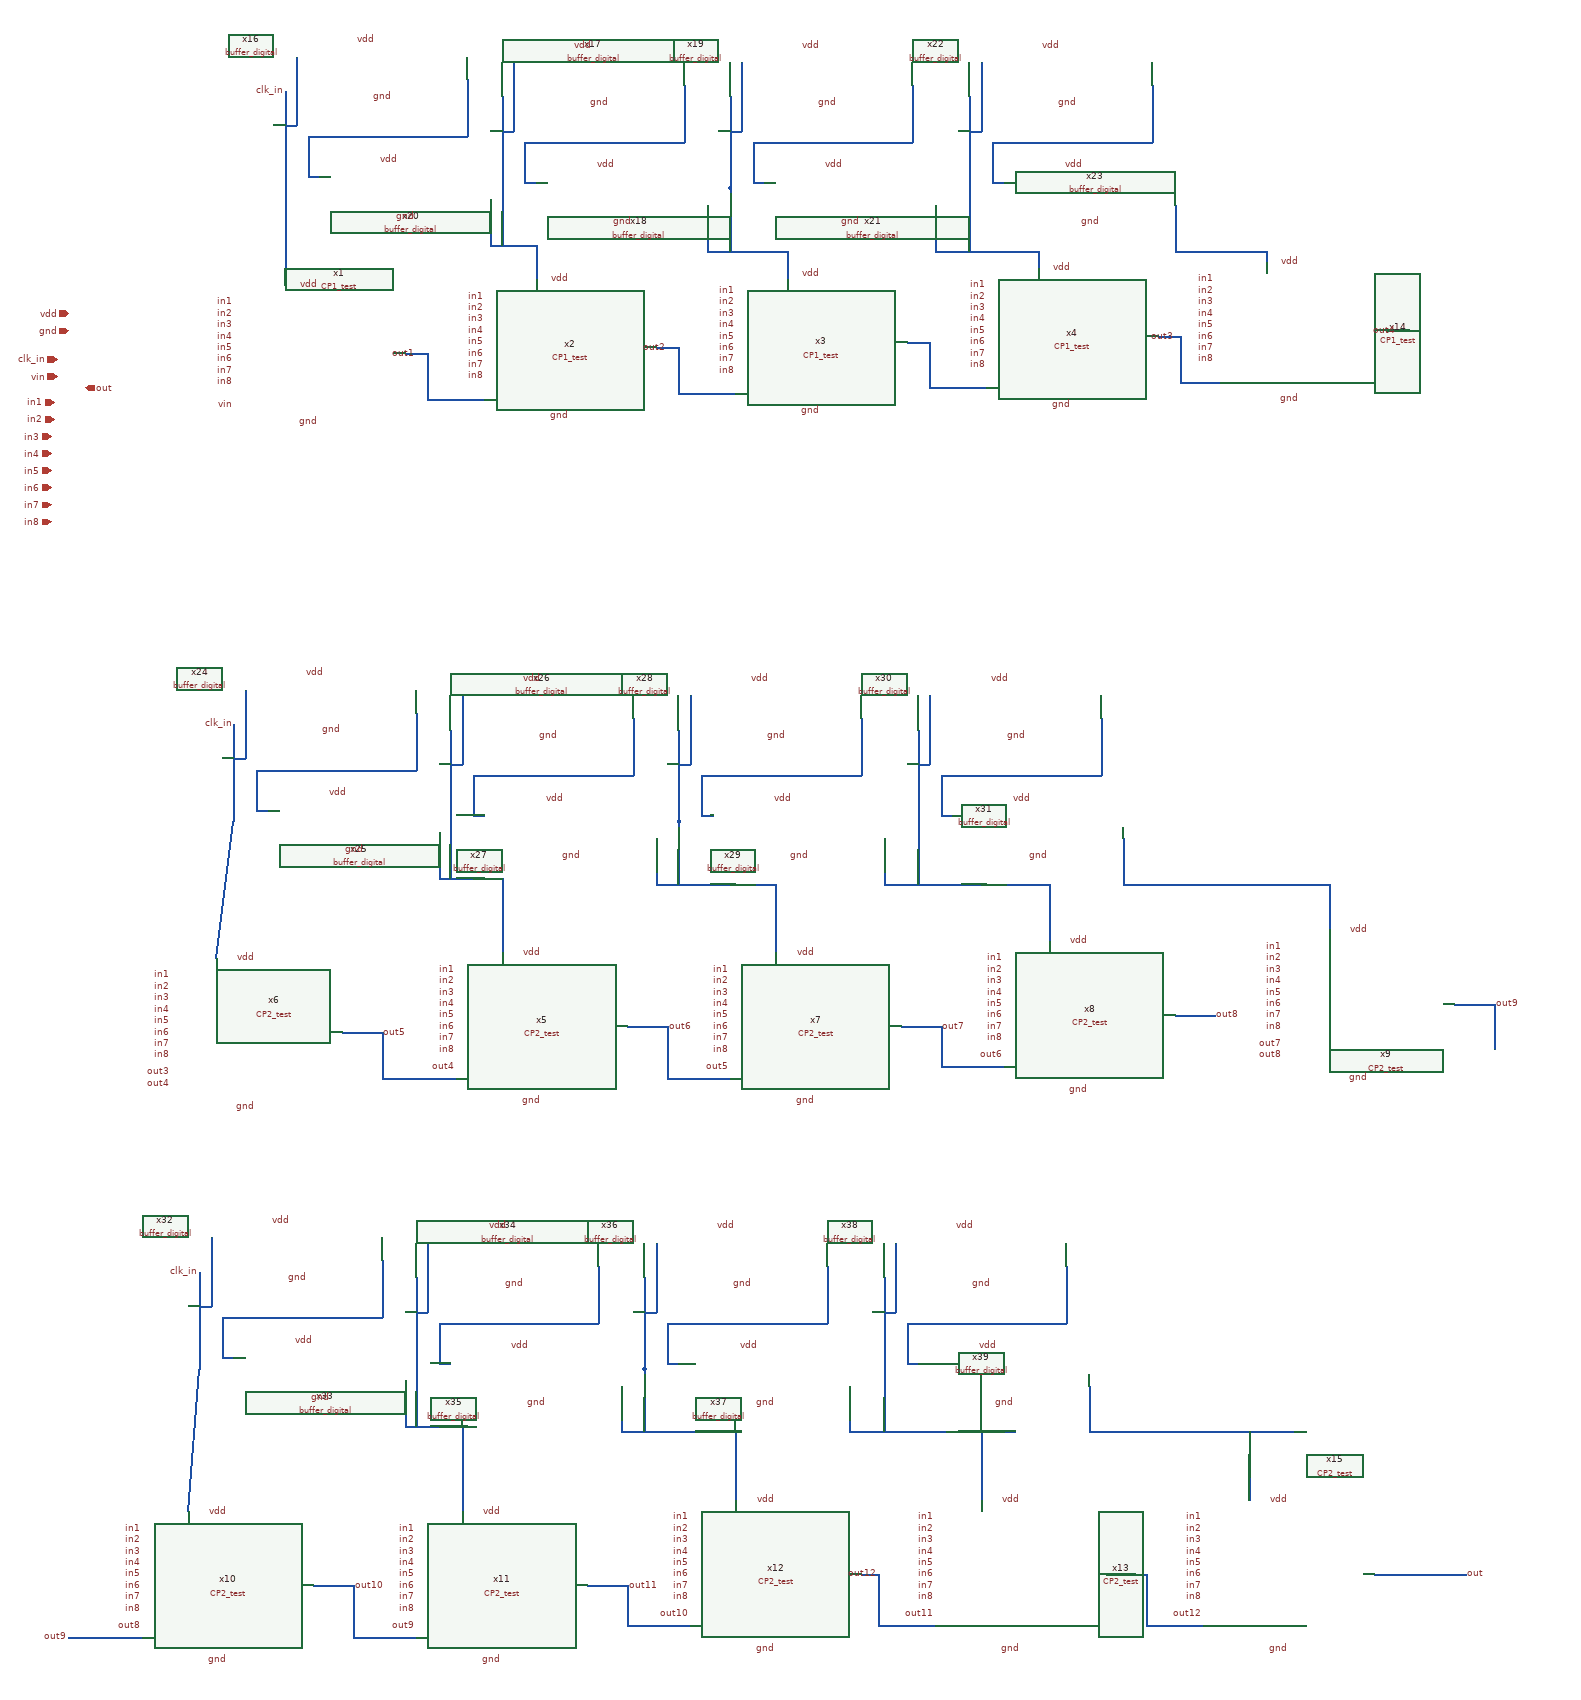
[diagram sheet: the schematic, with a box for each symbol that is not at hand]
v {xschem version=3.4.4 file_version=1.2
}
G {}
K {}
V {}
S {}
E {}
N -340 1800 -300 1800 {
lab=out1}
N 100 1790 140 1790 {
lab=out2}
N -300 1880 -200 1880 {
lab=out1}
N -300 1800 -300 1880 {
lab=out1}
N 540 1780 580 1780 {
lab=#net1}
N 140 1790 140 1870 {
lab=out2}
N 140 1870 240 1870 {
lab=out2}
N 980 1770 1020 1770 {
lab=out3}
N 580 1860 680 1860 {
lab=#net1}
N 580 1780 580 1860 {
lab=#net1}
N -450 2990 -380 2990 {
lab=out5}
N 50 2980 120 2980 {
lab=out6}
N 530 2980 600 2980 {
lab=out7}
N 1010 2960 1080 2960 {
lab=out8}
N -380 2990 -380 3070 {
lab=out5}
N -380 3070 -250 3070 {
lab=out5}
N 120 2980 120 3070 {
lab=out6}
N 120 3070 230 3070 {
lab=out6}
N 600 2980 600 3050 {
lab=out7}
N 600 3050 710 3050 {
lab=out7}
N 1500 2940 1570 2940 {
lab=out9}
N -500 3960 -430 3960 {
lab=out10}
N -20 3960 50 3960 {
lab=out11}
N 1570 2940 1570 3020 {
lab=out9}
N -930 4050 -800 4050 {
lab=out9}
N -430 3960 -430 4050 {
lab=out10}
N -430 4050 -320 4050 {
lab=out10}
N 50 3960 50 4030 {
lab=out11}
N 50 4030 160 4030 {
lab=out11}
N 460 3940 490 3940 {
lab=out12}
N 490 3940 490 4030 {
lab=out12}
N 490 4030 590 4030 {
lab=out12}
N 1380 1760 1420 1760 {
lab=out4}
N 1020 1770 1020 1850 {
lab=out3}
N 1020 1850 1090 1850 {
lab=out3}
N 1360 3940 1430 3940 {
lab=out}
N 930 3940 960 3940 {
lab=#net2}
N 960 3940 960 4030 {
lab=#net2}
N 960 4030 1060 4030 {
lab=#net2}
N 890 3940 940 3940 {
lab=#net2}
N 1430 3940 1520 3940 {
lab=out}
N -550 1500 -550 1510 {
lab=clk_in}
N -550 1510 -550 1670 {
lab=clk_in}
N -550 1660 -550 1680 {
lab=clk_in}
N -550 1340 -550 1500 {
lab=clk_in}
N -550 1400 -530 1400 {
lab=clk_in}
N -230 1360 -230 1420 {
lab=#net3}
N -510 1420 -230 1420 {
lab=#net3}
N -510 1420 -510 1490 {
lab=#net3}
N -510 1490 -490 1490 {
lab=#net3}
N -190 1610 -110 1610 {
lab=#net4}
N -110 1610 -110 1670 {
lab=#net4}
N -230 1320 -230 1350 {
lab=#net3}
N -230 1350 -230 1360 {
lab=#net3}
N -530 1280 -530 1400 {
lab=clk_in}
N -190 1530 -190 1610 {
lab=#net4}
N -170 1510 -170 1520 {
lab=#net4}
N -170 1350 -170 1510 {
lab=#net4}
N -170 1410 -150 1410 {
lab=#net4}
N 150 1370 150 1430 {
lab=#net5}
N -130 1430 150 1430 {
lab=#net5}
N -130 1430 -130 1500 {
lab=#net5}
N -130 1500 -110 1500 {
lab=#net5}
N 150 1330 150 1360 {
lab=#net5}
N 150 1360 150 1370 {
lab=#net5}
N -150 1290 -150 1410 {
lab=#net4}
N 190 1540 190 1620 {
lab=#net6}
N 230 1510 230 1520 {
lab=#net6}
N 230 1350 230 1510 {
lab=#net6}
N 230 1410 250 1410 {
lab=#net6}
N 550 1370 550 1430 {
lab=#net7}
N 270 1430 550 1430 {
lab=#net7}
N 270 1430 270 1500 {
lab=#net7}
N 270 1500 290 1500 {
lab=#net7}
N 550 1330 550 1360 {
lab=#net7}
N 550 1360 550 1370 {
lab=#net7}
N 250 1290 250 1410 {
lab=#net6}
N 590 1540 590 1620 {
lab=#net8}
N 650 1510 650 1520 {
lab=#net8}
N 650 1350 650 1510 {
lab=#net8}
N 650 1410 670 1410 {
lab=#net8}
N 970 1370 970 1430 {
lab=#net9}
N 690 1430 970 1430 {
lab=#net9}
N 690 1430 690 1500 {
lab=#net9}
N 690 1500 710 1500 {
lab=#net9}
N 970 1330 970 1360 {
lab=#net9}
N 970 1360 970 1370 {
lab=#net9}
N 670 1290 670 1410 {
lab=#net8}
N 1010 1540 1010 1620 {
lab=#net10}
N -170 1520 -170 1610 {
lab=#net4}
N 190 1620 330 1620 {
lab=#net6}
N 330 1620 330 1670 {
lab=#net6}
N 230 1510 230 1620 {
lab=#net6}
N 590 1620 770 1620 {
lab=#net8}
N 770 1620 770 1650 {
lab=#net8}
N 650 1520 650 1620 {
lab=#net8}
N 1010 1620 1170 1620 {
lab=#net10}
N 1170 1620 1170 1640 {
lab=#net10}
N -640 2610 -640 2620 {
lab=clk_in}
N -640 2450 -640 2610 {
lab=clk_in}
N -640 2510 -620 2510 {
lab=clk_in}
N -320 2470 -320 2530 {
lab=#net11}
N -600 2530 -320 2530 {
lab=#net11}
N -600 2530 -600 2600 {
lab=#net11}
N -600 2600 -580 2600 {
lab=#net11}
N -280 2720 -200 2720 {
lab=#net12}
N -320 2430 -320 2460 {
lab=#net11}
N -320 2460 -320 2470 {
lab=#net11}
N -620 2390 -620 2510 {
lab=clk_in}
N -280 2640 -280 2720 {
lab=#net12}
N -260 2620 -260 2630 {
lab=#net12}
N -260 2460 -260 2620 {
lab=#net12}
N -260 2520 -240 2520 {
lab=#net12}
N 60 2480 60 2540 {
lab=#net13}
N -220 2540 60 2540 {
lab=#net13}
N -220 2540 -220 2610 {
lab=#net13}
N -220 2610 -200 2610 {
lab=#net13}
N 60 2440 60 2470 {
lab=#net13}
N 60 2470 60 2480 {
lab=#net13}
N -240 2400 -240 2520 {
lab=#net12}
N 100 2650 100 2730 {
lab=#net14}
N 140 2620 140 2630 {
lab=#net14}
N 140 2460 140 2620 {
lab=#net14}
N 140 2520 160 2520 {
lab=#net14}
N 460 2480 460 2540 {
lab=#net15}
N 180 2540 460 2540 {
lab=#net15}
N 180 2540 180 2610 {
lab=#net15}
N 180 2610 200 2610 {
lab=#net15}
N 460 2440 460 2470 {
lab=#net15}
N 460 2470 460 2480 {
lab=#net15}
N 160 2400 160 2520 {
lab=#net14}
N 500 2650 500 2730 {
lab=#net16}
N 560 2620 560 2630 {
lab=#net16}
N 560 2460 560 2620 {
lab=#net16}
N 560 2520 580 2520 {
lab=#net16}
N 880 2480 880 2540 {
lab=#net17}
N 600 2540 880 2540 {
lab=#net17}
N 600 2540 600 2610 {
lab=#net17}
N 600 2610 620 2610 {
lab=#net17}
N 880 2440 880 2470 {
lab=#net17}
N 880 2470 880 2480 {
lab=#net17}
N 580 2400 580 2520 {
lab=#net16}
N 920 2650 920 2730 {
lab=#net18}
N -260 2630 -260 2720 {
lab=#net12}
N 100 2730 240 2730 {
lab=#net14}
N 140 2620 140 2730 {
lab=#net14}
N 500 2730 680 2730 {
lab=#net16}
N 560 2630 560 2730 {
lab=#net16}
N 920 2730 1080 2730 {
lab=#net18}
N -670 2860 -640 2620 {
lab=clk_in}
N -170 2720 -170 2850 {
lab=#net12}
N -220 2720 -170 2720 {
lab=#net12}
N 310 2730 310 2850 {
lab=#net14}
N 230 2730 310 2730 {
lab=#net14}
N 790 2730 790 2830 {
lab=#net16}
N 670 2730 790 2730 {
lab=#net16}
N 1080 2730 1280 2730 {
lab=#net18}
N 1280 2730 1280 2810 {
lab=#net18}
N -700 3570 -700 3580 {
lab=clk_in}
N -700 3410 -700 3570 {
lab=clk_in}
N -700 3470 -680 3470 {
lab=clk_in}
N -380 3430 -380 3490 {
lab=#net19}
N -660 3490 -380 3490 {
lab=#net19}
N -660 3490 -660 3560 {
lab=#net19}
N -660 3560 -640 3560 {
lab=#net19}
N -340 3680 -260 3680 {
lab=#net20}
N -380 3390 -380 3420 {
lab=#net19}
N -380 3420 -380 3430 {
lab=#net19}
N -680 3350 -680 3470 {
lab=clk_in}
N -340 3600 -340 3680 {
lab=#net20}
N -320 3580 -320 3590 {
lab=#net20}
N -320 3420 -320 3580 {
lab=#net20}
N -320 3480 -300 3480 {
lab=#net20}
N 0 3440 0 3500 {
lab=#net21}
N -280 3500 0 3500 {
lab=#net21}
N -280 3500 -280 3570 {
lab=#net21}
N -280 3570 -260 3570 {
lab=#net21}
N 0 3400 0 3430 {
lab=#net21}
N 0 3430 0 3440 {
lab=#net21}
N -300 3360 -300 3480 {
lab=#net20}
N 40 3610 40 3690 {
lab=#net22}
N 80 3580 80 3590 {
lab=#net22}
N 80 3420 80 3580 {
lab=#net22}
N 80 3480 100 3480 {
lab=#net22}
N 400 3440 400 3500 {
lab=#net23}
N 120 3500 400 3500 {
lab=#net23}
N 120 3500 120 3570 {
lab=#net23}
N 120 3570 140 3570 {
lab=#net23}
N 400 3400 400 3430 {
lab=#net23}
N 400 3430 400 3440 {
lab=#net23}
N 100 3360 100 3480 {
lab=#net22}
N 440 3610 440 3690 {
lab=#net24}
N 500 3580 500 3590 {
lab=#net24}
N 500 3420 500 3580 {
lab=#net24}
N 500 3480 520 3480 {
lab=#net24}
N 820 3440 820 3500 {
lab=#net25}
N 540 3500 820 3500 {
lab=#net25}
N 540 3500 540 3570 {
lab=#net25}
N 540 3570 560 3570 {
lab=#net25}
N 820 3400 820 3430 {
lab=#net25}
N 820 3430 820 3440 {
lab=#net25}
N 520 3360 520 3480 {
lab=#net24}
N 860 3610 860 3690 {
lab=#net26}
N -320 3590 -320 3680 {
lab=#net20}
N 40 3690 180 3690 {
lab=#net22}
N 80 3580 80 3690 {
lab=#net22}
N 440 3690 620 3690 {
lab=#net24}
N 500 3590 500 3690 {
lab=#net24}
N 860 3690 1020 3690 {
lab=#net26}
N -280 3680 -230 3680 {
lab=#net20}
N 170 3690 250 3690 {
lab=#net22}
N 610 3690 730 3690 {
lab=#net24}
N 1020 3690 1220 3690 {
lab=#net26}
N -720 3830 -700 3580 {
lab=clk_in}
N -240 3680 -240 3830 {
lab=#net20}
N 240 3690 240 3810 {
lab=#net22}
N 670 3690 670 3810 {
lab=#net24}
N 1140 3690 1140 3810 {
lab=#net26}
C {CP1_test.sym} -490 1800 0 0 {name=x1}
C {devices/lab_pin.sym} -490 1680 1 0 {name=p12 sig_type=std_logic lab=vdd}
C {devices/lab_pin.sym} -550 1340 1 0 {name=p13 sig_type=std_logic lab=clk_in}
C {devices/lab_pin.sym} -640 1710 0 0 {name=p14 sig_type=std_logic lab=in1
value=0}
C {devices/lab_pin.sym} -640 1730 0 0 {name=p15 sig_type=std_logic lab=in2
value=0}
C {devices/lab_pin.sym} -640 1750 0 0 {name=p16 sig_type=std_logic lab=in3
value=0}
C {devices/lab_pin.sym} -640 1770 0 0 {name=p17 sig_type=std_logic lab=in4
value=0}
C {devices/lab_pin.sym} -640 1790 0 0 {name=p18 sig_type=std_logic lab=in5
value=0}
C {devices/lab_pin.sym} -640 1810 0 0 {name=p19 sig_type=std_logic lab=in6
value=0}
C {devices/lab_pin.sym} -640 1830 0 0 {name=p20 sig_type=std_logic lab=in7
value=0}
C {devices/lab_pin.sym} -640 1850 0 0 {name=p21 sig_type=std_logic lab=in8
value=0}
C {devices/lab_pin.sym} -640 1890 0 0 {name=p22 sig_type=std_logic lab=vin}
C {CP1_test.sym} -50 1790 0 0 {name=x2}
C {devices/lab_pin.sym} -50 1670 1 0 {name=p23 sig_type=std_logic lab=vdd}
C {devices/lab_pin.sym} -200 1700 0 0 {name=p25 sig_type=std_logic lab=in1
value=0}
C {devices/lab_pin.sym} -200 1720 0 0 {name=p26 sig_type=std_logic lab=in2
value=0}
C {devices/lab_pin.sym} -200 1740 0 0 {name=p27 sig_type=std_logic lab=in3
value=0}
C {devices/lab_pin.sym} -200 1760 0 0 {name=p28 sig_type=std_logic lab=in4
value=0}
C {devices/lab_pin.sym} -200 1780 0 0 {name=p29 sig_type=std_logic lab=in5
value=0}
C {devices/lab_pin.sym} -200 1800 0 0 {name=p30 sig_type=std_logic lab=in6
value=0}
C {devices/lab_pin.sym} -200 1820 0 0 {name=p31 sig_type=std_logic lab=in7
value=0}
C {devices/lab_pin.sym} -200 1840 0 0 {name=p32 sig_type=std_logic lab=in8
value=0}
C {devices/lab_pin.sym} -320 1800 1 0 {name=p33 sig_type=std_logic lab=out1}
C {CP1_test.sym} 390 1780 0 0 {name=x3}
C {devices/lab_pin.sym} 390 1660 1 0 {name=p34 sig_type=std_logic lab=vdd}
C {devices/lab_pin.sym} 240 1690 0 0 {name=p36 sig_type=std_logic lab=in1
value=0}
C {devices/lab_pin.sym} 240 1710 0 0 {name=p37 sig_type=std_logic lab=in2
value=0}
C {devices/lab_pin.sym} 240 1730 0 0 {name=p38 sig_type=std_logic lab=in3
value=0}
C {devices/lab_pin.sym} 240 1750 0 0 {name=p39 sig_type=std_logic lab=in4
value=0}
C {devices/lab_pin.sym} 240 1770 0 0 {name=p40 sig_type=std_logic lab=in5
value=0}
C {devices/lab_pin.sym} 240 1790 0 0 {name=p41 sig_type=std_logic lab=in6
value=0}
C {devices/lab_pin.sym} 240 1810 0 0 {name=p42 sig_type=std_logic lab=in7
value=0}
C {devices/lab_pin.sym} 240 1830 0 0 {name=p43 sig_type=std_logic lab=in8
value=0}
C {CP1_test.sym} 830 1770 0 0 {name=x4}
C {devices/lab_pin.sym} 830 1650 1 0 {name=p44 sig_type=std_logic lab=vdd}
C {devices/lab_pin.sym} 680 1680 0 0 {name=p46 sig_type=std_logic lab=in1
value=0}
C {devices/lab_pin.sym} 680 1700 0 0 {name=p47 sig_type=std_logic lab=in2
value=0}
C {devices/lab_pin.sym} 680 1720 0 0 {name=p48 sig_type=std_logic lab=in3
value=0}
C {devices/lab_pin.sym} 680 1740 0 0 {name=p49 sig_type=std_logic lab=in4
value=0}
C {devices/lab_pin.sym} 680 1760 0 0 {name=p50 sig_type=std_logic lab=in5
value=0}
C {devices/lab_pin.sym} 680 1780 0 0 {name=p51 sig_type=std_logic lab=in6
value=0}
C {devices/lab_pin.sym} 680 1800 0 0 {name=p52 sig_type=std_logic lab=in7
value=0}
C {devices/lab_pin.sym} 680 1820 0 0 {name=p53 sig_type=std_logic lab=in8
value=0}
C {devices/lab_pin.sym} 120 1790 1 0 {name=p54 sig_type=std_logic lab=out2}
C {CP2_test.sym} -600 2990 0 0 {name=x6}
C {devices/lab_pin.sym} -750 2890 0 0 {name=p57 sig_type=std_logic lab=in1
value=0}
C {devices/lab_pin.sym} -750 2910 0 0 {name=p58 sig_type=std_logic lab=in2
value=0}
C {devices/lab_pin.sym} -750 2930 0 0 {name=p59 sig_type=std_logic lab=in3
value=0}
C {devices/lab_pin.sym} -750 2950 0 0 {name=p60 sig_type=std_logic lab=in4
value=0}
C {devices/lab_pin.sym} -750 2970 0 0 {name=p61 sig_type=std_logic lab=in5
value=0}
C {devices/lab_pin.sym} -750 2990 0 0 {name=p62 sig_type=std_logic lab=in6
value=0}
C {devices/lab_pin.sym} -750 3010 0 0 {name=p63 sig_type=std_logic lab=in7
value=0}
C {devices/lab_pin.sym} -750 3030 0 0 {name=p64 sig_type=std_logic lab=in8
value=0}
C {devices/lab_pin.sym} -750 3080 0 0 {name=p65 sig_type=std_logic lab=out4}
C {devices/lab_pin.sym} -750 3060 0 0 {name=p66 sig_type=std_logic lab=out3}
C {devices/lab_pin.sym} -600 2860 1 0 {name=p68 sig_type=std_logic lab=vdd}
C {devices/lab_pin.sym} -380 2990 2 0 {name=p69 sig_type=std_logic lab=out5}
C {CP2_test.sym} -100 2980 0 0 {name=x5}
C {devices/lab_pin.sym} -250 2880 0 0 {name=p70 sig_type=std_logic lab=in1
value=0}
C {devices/lab_pin.sym} -250 2900 0 0 {name=p71 sig_type=std_logic lab=in2
value=0}
C {devices/lab_pin.sym} -250 2920 0 0 {name=p72 sig_type=std_logic lab=in3
value=0}
C {devices/lab_pin.sym} -250 2940 0 0 {name=p73 sig_type=std_logic lab=in4
value=0}
C {devices/lab_pin.sym} -250 2960 0 0 {name=p74 sig_type=std_logic lab=in5
value=0}
C {devices/lab_pin.sym} -250 2980 0 0 {name=p75 sig_type=std_logic lab=in6
value=0}
C {devices/lab_pin.sym} -250 3000 0 0 {name=p76 sig_type=std_logic lab=in7
value=0}
C {devices/lab_pin.sym} -250 3020 0 0 {name=p77 sig_type=std_logic lab=in8
value=0}
C {devices/lab_pin.sym} -250 3050 0 0 {name=p78 sig_type=std_logic lab=out4}
C {devices/lab_pin.sym} -100 2850 1 0 {name=p80 sig_type=std_logic lab=vdd}
C {devices/lab_pin.sym} 120 2980 2 0 {name=p81 sig_type=std_logic lab=out6}
C {CP2_test.sym} 380 2980 0 0 {name=x7}
C {devices/lab_pin.sym} 230 2880 0 0 {name=p82 sig_type=std_logic lab=in1
value=0}
C {devices/lab_pin.sym} 230 2900 0 0 {name=p83 sig_type=std_logic lab=in2
value=0}
C {devices/lab_pin.sym} 230 2920 0 0 {name=p84 sig_type=std_logic lab=in3
value=0}
C {devices/lab_pin.sym} 230 2940 0 0 {name=p85 sig_type=std_logic lab=in4
value=0}
C {devices/lab_pin.sym} 230 2960 0 0 {name=p86 sig_type=std_logic lab=in5
value=0}
C {devices/lab_pin.sym} 230 2980 0 0 {name=p87 sig_type=std_logic lab=in6
value=0}
C {devices/lab_pin.sym} 230 3000 0 0 {name=p88 sig_type=std_logic lab=in7
value=0}
C {devices/lab_pin.sym} 230 3020 0 0 {name=p89 sig_type=std_logic lab=in8
value=0}
C {devices/lab_pin.sym} 230 3050 0 0 {name=p90 sig_type=std_logic lab=out5}
C {devices/lab_pin.sym} 380 2850 1 0 {name=p92 sig_type=std_logic lab=vdd}
C {devices/lab_pin.sym} 600 2980 2 0 {name=p93 sig_type=std_logic lab=out7}
C {CP2_test.sym} 860 2960 0 0 {name=x8}
C {devices/lab_pin.sym} 710 2860 0 0 {name=p94 sig_type=std_logic lab=in1
value=0}
C {devices/lab_pin.sym} 710 2880 0 0 {name=p95 sig_type=std_logic lab=in2
value=0}
C {devices/lab_pin.sym} 710 2900 0 0 {name=p96 sig_type=std_logic lab=in3
value=0}
C {devices/lab_pin.sym} 710 2920 0 0 {name=p97 sig_type=std_logic lab=in4
value=0}
C {devices/lab_pin.sym} 710 2940 0 0 {name=p98 sig_type=std_logic lab=in5
value=0}
C {devices/lab_pin.sym} 710 2960 0 0 {name=p99 sig_type=std_logic lab=in6
value=0}
C {devices/lab_pin.sym} 710 2980 0 0 {name=p100 sig_type=std_logic lab=in7
value=0}
C {devices/lab_pin.sym} 710 3000 0 0 {name=p101 sig_type=std_logic lab=in8
value=0}
C {devices/lab_pin.sym} 710 3030 0 0 {name=p102 sig_type=std_logic lab=out6}
C {devices/lab_pin.sym} 860 2830 1 0 {name=p104 sig_type=std_logic lab=vdd}
C {devices/lab_pin.sym} 1080 2960 2 0 {name=p105 sig_type=std_logic lab=out8}
C {CP2_test.sym} 1350 2940 0 0 {name=x9}
C {devices/lab_pin.sym} 1200 2840 0 0 {name=p106 sig_type=std_logic lab=in1
value=0}
C {devices/lab_pin.sym} 1200 2860 0 0 {name=p107 sig_type=std_logic lab=in2
value=0}
C {devices/lab_pin.sym} 1200 2880 0 0 {name=p108 sig_type=std_logic lab=in3
value=0}
C {devices/lab_pin.sym} 1200 2900 0 0 {name=p109 sig_type=std_logic lab=in4
value=0}
C {devices/lab_pin.sym} 1200 2920 0 0 {name=p110 sig_type=std_logic lab=in5
value=0}
C {devices/lab_pin.sym} 1200 2940 0 0 {name=p111 sig_type=std_logic lab=in6
value=0}
C {devices/lab_pin.sym} 1200 2960 0 0 {name=p112 sig_type=std_logic lab=in7
value=0}
C {devices/lab_pin.sym} 1200 2980 0 0 {name=p113 sig_type=std_logic lab=in8
value=0}
C {devices/lab_pin.sym} 1200 3030 0 0 {name=p114 sig_type=std_logic lab=out8}
C {devices/lab_pin.sym} 1200 3010 0 0 {name=p115 sig_type=std_logic lab=out7}
C {devices/lab_pin.sym} 1350 2810 1 0 {name=p117 sig_type=std_logic lab=vdd}
C {devices/lab_pin.sym} 1570 2940 2 0 {name=p118 sig_type=std_logic lab=out9}
C {CP2_test.sym} -650 3960 0 0 {name=x10}
C {devices/lab_pin.sym} -800 3860 0 0 {name=p119 sig_type=std_logic lab=in1
value=0}
C {devices/lab_pin.sym} -800 3880 0 0 {name=p120 sig_type=std_logic lab=in2
value=0}
C {devices/lab_pin.sym} -800 3900 0 0 {name=p121 sig_type=std_logic lab=in3
value=0}
C {devices/lab_pin.sym} -800 3920 0 0 {name=p122 sig_type=std_logic lab=in4
value=0}
C {devices/lab_pin.sym} -800 3940 0 0 {name=p123 sig_type=std_logic lab=in5
value=0}
C {devices/lab_pin.sym} -800 3960 0 0 {name=p124 sig_type=std_logic lab=in6
value=0}
C {devices/lab_pin.sym} -800 3980 0 0 {name=p125 sig_type=std_logic lab=in7
value=0}
C {devices/lab_pin.sym} -800 4000 0 0 {name=p126 sig_type=std_logic lab=in8
value=0}
C {devices/lab_pin.sym} -800 4030 0 0 {name=p127 sig_type=std_logic lab=out8}
C {devices/lab_pin.sym} -650 3830 1 0 {name=p129 sig_type=std_logic lab=vdd}
C {devices/lab_pin.sym} -430 3960 2 0 {name=p130 sig_type=std_logic lab=out10}
C {CP2_test.sym} -170 3960 0 0 {name=x11}
C {devices/lab_pin.sym} -320 3860 0 0 {name=p131 sig_type=std_logic lab=in1
value=0}
C {devices/lab_pin.sym} -320 3880 0 0 {name=p132 sig_type=std_logic lab=in2
value=0}
C {devices/lab_pin.sym} -320 3900 0 0 {name=p133 sig_type=std_logic lab=in3
value=0}
C {devices/lab_pin.sym} -320 3920 0 0 {name=p134 sig_type=std_logic lab=in4
value=0}
C {devices/lab_pin.sym} -320 3940 0 0 {name=p135 sig_type=std_logic lab=in5
value=0}
C {devices/lab_pin.sym} -320 3960 0 0 {name=p136 sig_type=std_logic lab=in6
value=0}
C {devices/lab_pin.sym} -320 3980 0 0 {name=p137 sig_type=std_logic lab=in7
value=0}
C {devices/lab_pin.sym} -320 4000 0 0 {name=p138 sig_type=std_logic lab=in8
value=0}
C {devices/lab_pin.sym} -320 4030 0 0 {name=p139 sig_type=std_logic lab=out9}
C {devices/lab_pin.sym} -170 3830 1 0 {name=p141 sig_type=std_logic lab=vdd}
C {devices/lab_pin.sym} 50 3960 2 0 {name=p142 sig_type=std_logic lab=out11}
C {CP2_test.sym} 310 3940 0 0 {name=x12}
C {devices/lab_pin.sym} 160 3840 0 0 {name=p143 sig_type=std_logic lab=in1
value=0}
C {devices/lab_pin.sym} 160 3860 0 0 {name=p144 sig_type=std_logic lab=in2
value=0}
C {devices/lab_pin.sym} 160 3880 0 0 {name=p145 sig_type=std_logic lab=in3
value=0}
C {devices/lab_pin.sym} 160 3900 0 0 {name=p146 sig_type=std_logic lab=in4
value=0}
C {devices/lab_pin.sym} 160 3920 0 0 {name=p147 sig_type=std_logic lab=in5
value=0}
C {devices/lab_pin.sym} 160 3940 0 0 {name=p148 sig_type=std_logic lab=in6
value=0}
C {devices/lab_pin.sym} 160 3960 0 0 {name=p149 sig_type=std_logic lab=in7
value=0}
C {devices/lab_pin.sym} 160 3980 0 0 {name=p150 sig_type=std_logic lab=in8
value=0}
C {devices/lab_pin.sym} 160 4010 0 0 {name=p151 sig_type=std_logic lab=out10}
C {devices/lab_pin.sym} 310 3810 1 0 {name=p153 sig_type=std_logic lab=vdd}
C {devices/lab_pin.sym} 1520 3940 2 0 {name=p154 sig_type=std_logic lab=out}
C {CP2_test.sym} 740 3940 0 0 {name=x13}
C {devices/lab_pin.sym} 590 3840 0 0 {name=p155 sig_type=std_logic lab=in1
value=0}
C {devices/lab_pin.sym} 590 3860 0 0 {name=p156 sig_type=std_logic lab=in2
value=0}
C {devices/lab_pin.sym} 590 3880 0 0 {name=p157 sig_type=std_logic lab=in3
value=0}
C {devices/lab_pin.sym} 590 3900 0 0 {name=p158 sig_type=std_logic lab=in4
value=0}
C {devices/lab_pin.sym} 590 3920 0 0 {name=p159 sig_type=std_logic lab=in5
value=0}
C {devices/lab_pin.sym} 590 3940 0 0 {name=p160 sig_type=std_logic lab=in6
value=0}
C {devices/lab_pin.sym} 590 3960 0 0 {name=p161 sig_type=std_logic lab=in7
value=0}
C {devices/lab_pin.sym} 590 3980 0 0 {name=p162 sig_type=std_logic lab=in8
value=0}
C {devices/lab_pin.sym} 590 4010 0 0 {name=p163 sig_type=std_logic lab=out11}
C {devices/lab_pin.sym} 740 3810 1 0 {name=p165 sig_type=std_logic lab=vdd}
C {devices/lab_pin.sym} 490 3940 1 0 {name=p166 sig_type=std_logic lab=out12}
C {devices/ipin.sym} -950 1810 0 0 {name=p1 lab=clk_in}
C {devices/iopin.sym} -930 1760 0 0 {name=p2 lab=gnd}
C {devices/iopin.sym} -930 1730 0 0 {name=p3 lab=vdd}
C {devices/opin.sym} -900 1860 0 0 {name=p4 lab=out}
C {devices/ipin.sym} -950 1840 0 0 {name=p5 lab=vin}
C {devices/ipin.sym} -955 1885 0 0 {name=p6 lab=in1}
C {devices/ipin.sym} -955 1915 0 0 {name=p7 lab=in2}
C {devices/ipin.sym} -960 1945 0 0 {name=p8 lab=in3}
C {devices/ipin.sym} -960 1975 0 0 {name=p9 lab=in4}
C {devices/ipin.sym} -960 2005 0 0 {name=p10 lab=in5}
C {devices/ipin.sym} -960 2035 0 0 {name=p11 lab=in6}
C {devices/ipin.sym} -960 2065 0 0 {name=p167 lab=in7}
C {devices/ipin.sym} -960 2095 0 0 {name=p168 lab=in8}
C {CP1_test.sym} 1230 1760 0 0 {name=x14}
C {devices/lab_pin.sym} 1230 1640 1 0 {name=p169 sig_type=std_logic lab=vdd}
C {devices/lab_pin.sym} 1080 1670 0 0 {name=p171 sig_type=std_logic lab=in1
value=0}
C {devices/lab_pin.sym} 1080 1690 0 0 {name=p172 sig_type=std_logic lab=in2
value=0}
C {devices/lab_pin.sym} 1080 1710 0 0 {name=p173 sig_type=std_logic lab=in3
value=0}
C {devices/lab_pin.sym} 1080 1730 0 0 {name=p174 sig_type=std_logic lab=in4
value=0}
C {devices/lab_pin.sym} 1080 1750 0 0 {name=p175 sig_type=std_logic lab=in5
value=0}
C {devices/lab_pin.sym} 1080 1770 0 0 {name=p176 sig_type=std_logic lab=in6
value=0}
C {devices/lab_pin.sym} 1080 1790 0 0 {name=p177 sig_type=std_logic lab=in7
value=0}
C {devices/lab_pin.sym} 1080 1810 0 0 {name=p178 sig_type=std_logic lab=in8
value=0}
C {devices/lab_pin.sym} 1400 1760 1 0 {name=p179 sig_type=std_logic lab=out4}
C {devices/lab_pin.sym} 1010 1770 1 0 {name=p56 sig_type=std_logic lab=out3}
C {CP2_test.sym} 1210 3940 0 0 {name=x15}
C {devices/lab_pin.sym} 1060 3840 0 0 {name=p55 sig_type=std_logic lab=in1
value=0}
C {devices/lab_pin.sym} 1060 3860 0 0 {name=p180 sig_type=std_logic lab=in2
value=0}
C {devices/lab_pin.sym} 1060 3880 0 0 {name=p181 sig_type=std_logic lab=in3
value=0}
C {devices/lab_pin.sym} 1060 3900 0 0 {name=p182 sig_type=std_logic lab=in4
value=0}
C {devices/lab_pin.sym} 1060 3920 0 0 {name=p183 sig_type=std_logic lab=in5
value=0}
C {devices/lab_pin.sym} 1060 3940 0 0 {name=p184 sig_type=std_logic lab=in6
value=0}
C {devices/lab_pin.sym} 1060 3960 0 0 {name=p185 sig_type=std_logic lab=in7
value=0}
C {devices/lab_pin.sym} 1060 3980 0 0 {name=p186 sig_type=std_logic lab=in8
value=0}
C {devices/lab_pin.sym} 1060 4010 0 0 {name=p187 sig_type=std_logic lab=out12}
C {devices/lab_pin.sym} 1210 3810 1 0 {name=p189 sig_type=std_logic lab=vdd}
C {devices/lab_pin.sym} -490 1920 3 0 {name=p190 sig_type=std_logic lab=gnd}
C {devices/lab_pin.sym} -50 1910 3 0 {name=p191 sig_type=std_logic lab=gnd}
C {devices/lab_pin.sym} 390 1900 3 0 {name=p192 sig_type=std_logic lab=gnd}
C {devices/lab_pin.sym} 830 1890 3 0 {name=p193 sig_type=std_logic lab=gnd}
C {devices/lab_pin.sym} 1230 1880 3 0 {name=p194 sig_type=std_logic lab=gnd}
C {devices/lab_pin.sym} 860 3090 3 0 {name=p195 sig_type=std_logic lab=gnd}
C {devices/lab_pin.sym} 380 3110 3 0 {name=p196 sig_type=std_logic lab=gnd}
C {devices/lab_pin.sym} -100 3110 3 0 {name=p197 sig_type=std_logic lab=gnd}
C {devices/lab_pin.sym} -600 3120 3 0 {name=p198 sig_type=std_logic lab=gnd}
C {devices/lab_pin.sym} 1350 3070 3 0 {name=p199 sig_type=std_logic lab=gnd}
C {devices/lab_pin.sym} -650 4090 3 0 {name=p200 sig_type=std_logic lab=gnd}
C {devices/lab_pin.sym} -170 4090 3 0 {name=p201 sig_type=std_logic lab=gnd}
C {devices/lab_pin.sym} 310 4070 3 0 {name=p202 sig_type=std_logic lab=gnd}
C {devices/lab_pin.sym} 740 4070 3 0 {name=p203 sig_type=std_logic lab=gnd}
C {devices/lab_pin.sym} 1210 4070 3 0 {name=p204 sig_type=std_logic lab=gnd}
C {buffer_digital.sym} -380 1300 0 0 {name=x16}
C {buffer_digital.sym} -340 1510 0 0 {name=x20}
C {devices/lab_pin.sym} -390 1250 1 0 {name=p24 sig_type=std_logic lab=vdd}
C {devices/lab_pin.sym} -350 1460 1 0 {name=p35 sig_type=std_logic lab=vdd}
C {devices/lab_pin.sym} -360 1350 3 0 {name=p45 sig_type=std_logic lab=gnd}
C {devices/lab_pin.sym} -320 1560 3 0 {name=p170 sig_type=std_logic lab=gnd}
C {buffer_digital.sym} 0 1310 0 0 {name=x17}
C {buffer_digital.sym} 40 1520 0 0 {name=x18}
C {devices/lab_pin.sym} -10 1260 1 0 {name=p205 sig_type=std_logic lab=vdd}
C {devices/lab_pin.sym} 30 1470 1 0 {name=p206 sig_type=std_logic lab=vdd}
C {devices/lab_pin.sym} 20 1360 3 0 {name=p207 sig_type=std_logic lab=gnd}
C {devices/lab_pin.sym} 60 1570 3 0 {name=p208 sig_type=std_logic lab=gnd}
C {buffer_digital.sym} 400 1310 0 0 {name=x19}
C {buffer_digital.sym} 440 1520 0 0 {name=x21}
C {devices/lab_pin.sym} 390 1260 1 0 {name=p209 sig_type=std_logic lab=vdd}
C {devices/lab_pin.sym} 430 1470 1 0 {name=p210 sig_type=std_logic lab=vdd}
C {devices/lab_pin.sym} 420 1360 3 0 {name=p211 sig_type=std_logic lab=gnd}
C {devices/lab_pin.sym} 460 1570 3 0 {name=p212 sig_type=std_logic lab=gnd}
C {buffer_digital.sym} 820 1310 0 0 {name=x22}
C {buffer_digital.sym} 860 1520 0 0 {name=x23}
C {devices/lab_pin.sym} 810 1260 1 0 {name=p213 sig_type=std_logic lab=vdd}
C {devices/lab_pin.sym} 850 1470 1 0 {name=p214 sig_type=std_logic lab=vdd}
C {devices/lab_pin.sym} 840 1360 3 0 {name=p215 sig_type=std_logic lab=gnd}
C {devices/lab_pin.sym} 880 1570 3 0 {name=p216 sig_type=std_logic lab=gnd}
C {devices/lab_pin.sym} -640 2450 1 0 {name=p217 sig_type=std_logic lab=clk_in}
C {buffer_digital.sym} -470 2410 0 0 {name=x24}
C {buffer_digital.sym} -430 2620 0 0 {name=x25}
C {devices/lab_pin.sym} -480 2360 1 0 {name=p218 sig_type=std_logic lab=vdd}
C {devices/lab_pin.sym} -440 2570 1 0 {name=p219 sig_type=std_logic lab=vdd}
C {devices/lab_pin.sym} -450 2460 3 0 {name=p220 sig_type=std_logic lab=gnd}
C {devices/lab_pin.sym} -410 2670 3 0 {name=p221 sig_type=std_logic lab=gnd}
C {buffer_digital.sym} -90 2420 0 0 {name=x26}
C {buffer_digital.sym} -50 2630 0 0 {name=x27}
C {devices/lab_pin.sym} -100 2370 1 0 {name=p222 sig_type=std_logic lab=vdd}
C {devices/lab_pin.sym} -60 2580 1 0 {name=p223 sig_type=std_logic lab=vdd}
C {devices/lab_pin.sym} -70 2470 3 0 {name=p224 sig_type=std_logic lab=gnd}
C {devices/lab_pin.sym} -30 2680 3 0 {name=p225 sig_type=std_logic lab=gnd}
C {buffer_digital.sym} 310 2420 0 0 {name=x28}
C {buffer_digital.sym} 350 2630 0 0 {name=x29}
C {devices/lab_pin.sym} 300 2370 1 0 {name=p226 sig_type=std_logic lab=vdd}
C {devices/lab_pin.sym} 340 2580 1 0 {name=p227 sig_type=std_logic lab=vdd}
C {devices/lab_pin.sym} 330 2470 3 0 {name=p228 sig_type=std_logic lab=gnd}
C {devices/lab_pin.sym} 370 2680 3 0 {name=p229 sig_type=std_logic lab=gnd}
C {buffer_digital.sym} 730 2420 0 0 {name=x30}
C {buffer_digital.sym} 770 2630 0 0 {name=x31}
C {devices/lab_pin.sym} 720 2370 1 0 {name=p230 sig_type=std_logic lab=vdd}
C {devices/lab_pin.sym} 760 2580 1 0 {name=p231 sig_type=std_logic lab=vdd}
C {devices/lab_pin.sym} 750 2470 3 0 {name=p232 sig_type=std_logic lab=gnd}
C {devices/lab_pin.sym} 790 2680 3 0 {name=p233 sig_type=std_logic lab=gnd}
C {devices/lab_pin.sym} -930 4050 0 0 {name=p67 sig_type=std_logic lab=out9}
C {devices/lab_pin.sym} -700 3410 1 0 {name=p79 sig_type=std_logic lab=clk_in}
C {buffer_digital.sym} -530 3370 0 0 {name=x32}
C {buffer_digital.sym} -490 3580 0 0 {name=x33}
C {devices/lab_pin.sym} -540 3320 1 0 {name=p91 sig_type=std_logic lab=vdd}
C {devices/lab_pin.sym} -500 3530 1 0 {name=p103 sig_type=std_logic lab=vdd}
C {devices/lab_pin.sym} -510 3420 3 0 {name=p116 sig_type=std_logic lab=gnd}
C {devices/lab_pin.sym} -470 3630 3 0 {name=p234 sig_type=std_logic lab=gnd}
C {buffer_digital.sym} -150 3380 0 0 {name=x34}
C {buffer_digital.sym} -110 3590 0 0 {name=x35}
C {devices/lab_pin.sym} -160 3330 1 0 {name=p235 sig_type=std_logic lab=vdd}
C {devices/lab_pin.sym} -120 3540 1 0 {name=p236 sig_type=std_logic lab=vdd}
C {devices/lab_pin.sym} -130 3430 3 0 {name=p237 sig_type=std_logic lab=gnd}
C {devices/lab_pin.sym} -90 3640 3 0 {name=p238 sig_type=std_logic lab=gnd}
C {buffer_digital.sym} 250 3380 0 0 {name=x36}
C {buffer_digital.sym} 290 3590 0 0 {name=x37}
C {devices/lab_pin.sym} 240 3330 1 0 {name=p239 sig_type=std_logic lab=vdd}
C {devices/lab_pin.sym} 280 3540 1 0 {name=p240 sig_type=std_logic lab=vdd}
C {devices/lab_pin.sym} 270 3430 3 0 {name=p241 sig_type=std_logic lab=gnd}
C {devices/lab_pin.sym} 310 3640 3 0 {name=p242 sig_type=std_logic lab=gnd}
C {buffer_digital.sym} 670 3380 0 0 {name=x38}
C {buffer_digital.sym} 710 3590 0 0 {name=x39}
C {devices/lab_pin.sym} 660 3330 1 0 {name=p243 sig_type=std_logic lab=vdd}
C {devices/lab_pin.sym} 700 3540 1 0 {name=p244 sig_type=std_logic lab=vdd}
C {devices/lab_pin.sym} 690 3430 3 0 {name=p245 sig_type=std_logic lab=gnd}
C {devices/lab_pin.sym} 730 3640 3 0 {name=p246 sig_type=std_logic lab=gnd}
